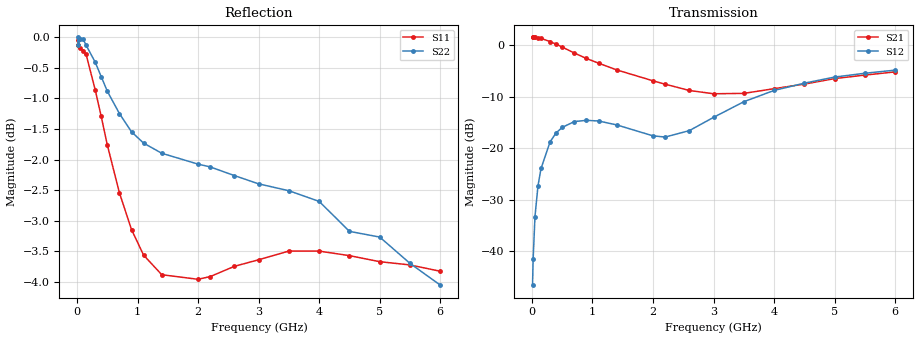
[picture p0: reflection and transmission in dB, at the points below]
! Infineon Technologies  Discrete & RF Semiconductors
! BFS17W
! Si NPN RF Bipolar Junction Transistor in SOT323
! VCE = 3 V  IC = 0.3 mA
! Common Emitter S-Parameters:  August  1999
# GHz  S  MA  R  50
!  f  S11  S21  S12  S22
! GHz  MAG  ANG  MAG  ANG  MAG  ANG  MAG  ANG
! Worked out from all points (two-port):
!   36 points, 10 MHz to 6 GHz, reference 50 ohm
!   highest |S21| = 1.55 dB at 50 MHz (marker M1); lowest = -9.4 dB at 3 GHz (marker M2)
!   |S21| within 3 dB of the highest: start of sweep to 692.9 MHz
!   lowest |S11| = -4.0 dB at 2 GHz (marker M3), VSWR 4.46, Z = 11.2 + j2.9 ohm
!   |S11| at or under -10 dB: nowhere
!   |S22| runs from -4.1 to 0.0 dB; largest |S21 - S12| = 1.2
!   S11 on the Smith chart (normalised r, x): 10 MHz: 30, -56; 300 MHz: 0.27, -2.11; 700 MHz: 0.24, -0.79; 1.4 GHz: 0.23, -0.20; 3 GHz: 0.24, +0.39; 6 GHz: 0.51, +1.10
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0.01  0.9851 -1.6  1.193 179.3  0.0047 88.9  0.9999 0.0
0.02  0.9941 -3.7  1.194 177.1  0.0084 90.6  0.9856 -0.9
0.05  0.9799 -8.8  1.196 172.5  0.0217 85.1  0.9969 -2.6
0.1  0.975 -17.0  1.18 165.5  0.0433 79.1  0.9963 -5.1
0.15  0.9685 -26.4  1.17 157.7  0.0638 73.3  0.9854 -7.6
0.3  0.9059 -50.1  1.089 137.1  0.1157 59.4  0.9542 -14.2
0.4  0.8615 -64.7  1.027 124.4  0.1415 51.1  0.9286 -18.1
0.5  0.8166 -78.1  0.964 113.4  0.1598 43.7  0.9035 -21.4
0.7  0.7462 -101.4  0.843 94.6  0.1821 32.8  0.8663 -27.3
0.9  0.6962 -120.5  0.747 79.6  0.1872 24.6  0.8369 -32.9
1.1  0.6634 -136.7  0.672 67.3  0.1845 19.1  0.8193 -38.3
1.4  0.6394 -156.5  0.578 53.1  0.169 14.9  0.8038 -46.7
2  0.6339 173.0  0.453 35.3  0.1323 25.0  0.7875 -64.9
2.2  0.6372 164.7  0.42 32.0  0.1288 33.9  0.7834 -71.1
2.6  0.6496 149.4  0.365 29.3  0.1487 52.8  0.7707 -84.1
3  0.6577 135.9  0.339 31.3  0.2001 62.1  0.7588 -96.6
3.5  0.6686 121.2  0.342 36.1  0.2838 62.6  0.749 -112.8
4  0.6685 108.9  0.38 38.6  0.3654 56.9  0.7341 -129.8
4.5  0.6628 98.3  0.421 37.7  0.4298 49.7  0.6938 -145.5
5  0.6553 90.3  0.476 34.2  0.4925 42.7  0.6864 -159.0
5.5  0.6513 83.5  0.515 30.0  0.5363 35.9  0.6532 -172.8
6  0.6436 78.1  0.553 25.4  0.5751 29.5  0.627 175.2
